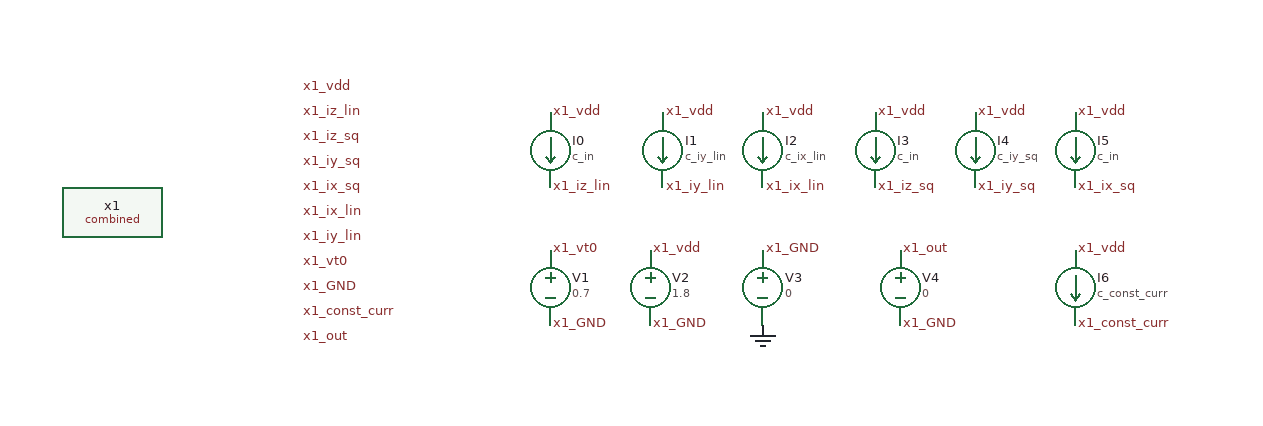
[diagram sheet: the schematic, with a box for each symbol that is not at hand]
v {xschem version=3.4.8RC file_version=1.3}
G {}
K {}
V {}
S {}
F {}
E {}
C {isource.sym} 370 -30 0 0 {name=I0 value=c_in
}
C {isource.sym} 460 -30 0 0 {name=I1 value=c_iy_lin}
C {isource.sym} 540 -30 0 0 {name=I2 value=c_ix_lin}
C {isource.sym} 630 -30 0 0 {name=I3 value=c_in

}
C {isource.sym} 710 -30 0 0 {name=I4 value=c_iy_sq
}
C {isource.sym} 790 -30 0 0 {name=I5 value=c_in}
C {vsource.sym} 370 80 0 0 {name=V1 value=0.7 savecurrent=false}
C {vsource.sym} 450 80 0 0 {name=V2 value=1.8 savecurrent=false}
C {vsource.sym} 540 80 0 0 {name=V3 value=0 savecurrent=false}
C {gnd.sym} 540 110 0 0 {name=l1 lab=0}
C {lab_wire.sym} 540 50 0 1 {name=p11 lab=x1_GND}
C {lab_wire.sym} 450 110 0 1 {name=p12 lab=x1_GND}
C {lab_wire.sym} 370 110 0 1 {name=p13 lab=x1_GND}
C {lab_wire.sym} 450 50 0 1 {name=p14 lab=x1_vdd}
C {lab_wire.sym} 370 -60 0 1 {name=p15 lab=x1_vdd}
C {lab_wire.sym} 460 -60 0 1 {name=p16 lab=x1_vdd}
C {lab_wire.sym} 540 -60 0 1 {name=p17 lab=x1_vdd}
C {lab_wire.sym} 630 -60 0 1 {name=p18 lab=x1_vdd}
C {lab_wire.sym} 710 -60 0 1 {name=p19 lab=x1_vdd}
C {lab_wire.sym} 790 -60 0 1 {name=p20 lab=x1_vdd}
C {lab_wire.sym} 370 50 0 1 {name=p21 lab=x1_vt0}
C {lab_wire.sym} 370 0 0 1 {name=p22 lab=x1_iz_lin}
C {lab_wire.sym} 630 0 0 1 {name=p23 lab=x1_iz_sq}
C {lab_wire.sym} 710 0 0 1 {name=p24 lab=x1_iy_sq}
C {lab_wire.sym} 790 0 0 1 {name=p25 lab=x1_ix_sq}
C {lab_wire.sym} 460 0 0 1 {name=p26 lab=x1_iy_lin}
C {lab_wire.sym} 540 0 0 1 {name=p27 lab=x1_ix_lin}
C {isource.sym} 790 80 0 0 {name=I6 value=c_const_curr}
C {lab_wire.sym} 790 50 0 1 {name=p31 lab=x1_vdd}
C {lab_wire.sym} 790 110 0 1 {name=p32 lab=x1_const_curr}
C {combined.sym} 20 20 0 0 {name=x1}
C {lab_wire.sym} 170 -80 0 1 {name=p1 lab=x1_vdd}
C {lab_wire.sym} 170 -60 0 1 {name=p2 lab=x1_iz_lin}
C {lab_wire.sym} 170 -40 0 1 {name=p3 lab=x1_iz_sq}
C {lab_wire.sym} 170 -20 0 1 {name=p4 lab=x1_iy_sq}
C {lab_wire.sym} 170 0 0 1 {name=p5 lab=x1_ix_sq}
C {lab_wire.sym} 170 20 0 1 {name=p6 lab=x1_ix_lin}
C {lab_wire.sym} 170 40 0 1 {name=p7 lab=x1_iy_lin}
C {lab_wire.sym} 170 60 0 1 {name=p8 lab=x1_vt0}
C {lab_wire.sym} 170 80 0 1 {name=p9 lab=x1_GND}
C {lab_wire.sym} 170 100 0 1 {name=p10 lab=x1_const_curr}
C {lab_wire.sym} 170 120 0 1 {name=p28 lab=x1_out}
C {vsource.sym} 650 80 0 0 {name=V4 value=0 savecurrent=false}
C {lab_wire.sym} 650 50 0 1 {name=p29 lab=x1_out}
C {lab_wire.sym} 650 110 0 1 {name=p30 lab=x1_GND}
